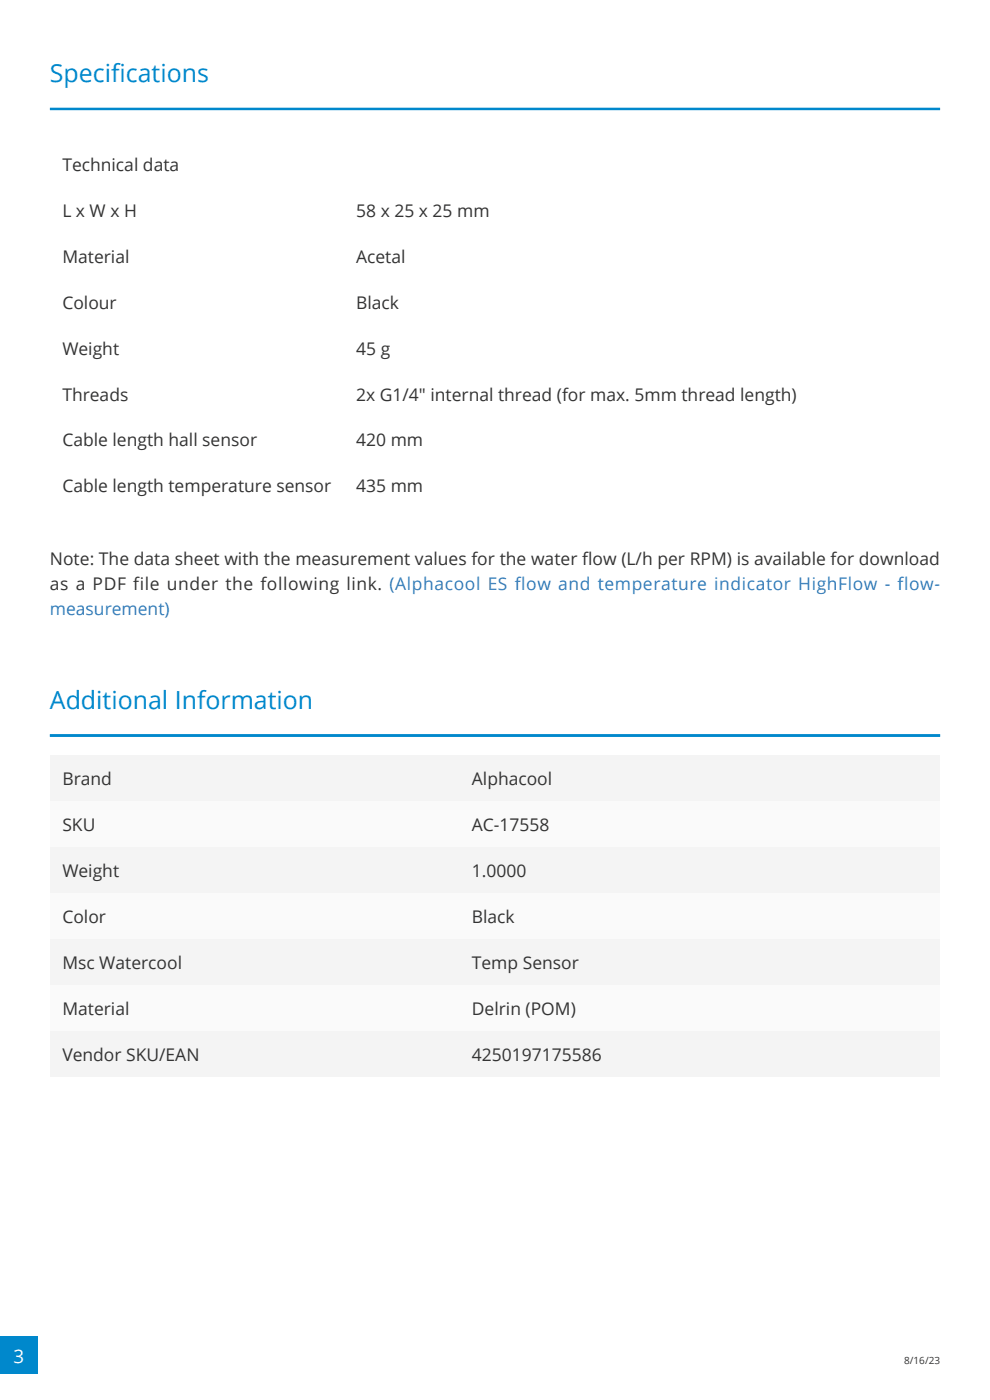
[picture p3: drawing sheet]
<svg xmlns="http://www.w3.org/2000/svg" width="210mm" height="297mm" viewBox="0 0 210 297" stroke-linecap="round" stroke-linejoin="round" font-family="sans-serif">
<defs><g id="words">
<g font-size="5.3" fill="#08c">
<text x="10.6" y="17.5">Specifications</text>
<text x="10.6" y="150.4">Additional Information</text>
</g>
<text font-size="4" fill="#fff" x="2.8" y="289">3</text>
<g font-size="3.7" fill="#333">
<text x="13.2" y="36.3">Technical data</text>
<text x="13.2" y="46">L x W x H</text>
<text x="75.6" y="46">58 x 25 x 25 mm</text>
<text x="13.2" y="55.8">Material</text>
<text x="75.6" y="55.8">Acetal</text>
<text x="13.2" y="65.5">Colour</text>
<text x="75.6" y="65.5">Black</text>
<text x="13.2" y="75.2">Weight</text>
<text x="75.6" y="75.2">45 g</text>
<text x="13.2" y="85">Threads</text>
<text x="75.6" y="85">2x G1/4&quot; internal thread (for max. 5mm thread length)</text>
<text x="13.2" y="94.7">Cable length hall sensor</text>
<text x="75.6" y="94.7">420 mm</text>
<text x="13.2" y="104.5">Cable length temperature sensor</text>
<text x="75.6" y="104.5">435 mm</text>
<text x="10.6" y="119.9">Note: The data sheet with the measurement values for the water flow (L/h per RPM) is available for download</text>
<text x="10.6" y="125.2">as a PDF file under the following link. (Alphacool ES flow and temperature indicator HighFlow - flow-</text>
<text x="13.2" y="166.6">Brand</text>
<text x="100.1" y="166.6">Alphacool</text>
<text x="13.2" y="176.3">SKU</text>
<text x="100.1" y="176.3">AC-17558</text>
<text x="13.2" y="186.1">Weight</text>
<text x="100.1" y="186.1">1.0000</text>
<text x="13.2" y="195.8">Color</text>
<text x="100.1" y="195.8">Black</text>
<text x="13.2" y="205.5">Msc Watercool</text>
<text x="100.1" y="205.5">Temp Sensor</text>
<text x="13.2" y="215.3">Material</text>
<text x="100.1" y="215.3">Delrin (POM)</text>
<text x="13.2" y="225">Vendor SKU/EAN</text>
<text x="100.1" y="225">4250197175586</text>
</g>
<text font-size="3.7" fill="#337ab7" x="10.6" y="130.5">measurement)</text>
<text font-size="2.1" fill="#333" x="191.8" y="289.3">8/16/23</text>
</g></defs>
<path d="M0 283.5h7.9v8h-7.9z" fill="#08c"/>
<path d="M10.6 23.1h188.8" fill="none" stroke="#08c" stroke-width=".53"/>
<g fill="#f4f4f4">
<path d="M10.6 160.3h86.8v9.7h-86.8z"/>
<path d="M97.4 160.3h102v9.7h-102z"/>
</g>
<g fill="#fafafa">
<path d="M10.6 170h86.8v9.7h-86.8z"/>
<path d="M97.4 170h102v9.7h-102z"/>
</g>
<g fill="#f4f4f4">
<path d="M10.6 179.7h86.8v9.8h-86.8z"/>
<path d="M97.4 179.7h102v9.8h-102z"/>
</g>
<g fill="#fafafa">
<path d="M10.6 189.5h86.8v9.7h-86.8z"/>
<path d="M97.4 189.5h102v9.7h-102z"/>
</g>
<g fill="#f4f4f4">
<path d="M10.6 199.2h86.8v9.8h-86.8z"/>
<path d="M97.4 199.2h102v9.8h-102z"/>
</g>
<g fill="#fafafa">
<path d="M10.6 209h86.8v9.7h-86.8z"/>
<path d="M97.4 209h102v9.7h-102z"/>
</g>
<g fill="#f4f4f4">
<path d="M10.6 218.7h86.8v9.7h-86.8z"/>
<path d="M97.4 218.7h102v9.7h-102z"/>
<path d="M10.6 160.3h86.8v9.7h-86.8z"/>
<path d="M97.4 160.3h102v9.7h-102z"/>
</g>
<g fill="#fafafa">
<path d="M10.6 170h86.8v9.7h-86.8z"/>
<path d="M97.4 170h102v9.7h-102z"/>
</g>
<g fill="#f4f4f4">
<path d="M10.6 179.7h86.8v9.8h-86.8z"/>
<path d="M97.4 179.7h102v9.8h-102z"/>
</g>
<g fill="#fafafa">
<path d="M10.6 189.5h86.8v9.7h-86.8z"/>
<path d="M97.4 189.5h102v9.7h-102z"/>
</g>
<g fill="#f4f4f4">
<path d="M10.6 199.2h86.8v9.8h-86.8z"/>
<path d="M97.4 199.2h102v9.8h-102z"/>
</g>
<g fill="#fafafa">
<path d="M10.6 209h86.8v9.7h-86.8z"/>
<path d="M97.4 209h102v9.7h-102z"/>
</g>
<g fill="#f4f4f4">
<path d="M10.6 218.7h86.8v9.7h-86.8z"/>
<path d="M97.4 218.7h102v9.7h-102z"/>
</g>
<g fill="#fff">
<path d="M10.6 144.9h188.8z"/>
<path d="M10.6 144.9h188.8v6.9h-188.8z"/>
<path d="M10.6 151.8h188.8v4.5h-188.8z"/>
</g>
<path d="M10.6 156h188.8" fill="none" stroke="#08c" stroke-width=".53"/>
<use href="#words"/>
</svg>
